VERSION 5.7 ;
  NOWIREEXTENSIONATPIN ON ;
  DIVIDERCHAR "/" ;
  BUSBITCHARS "[]" ;
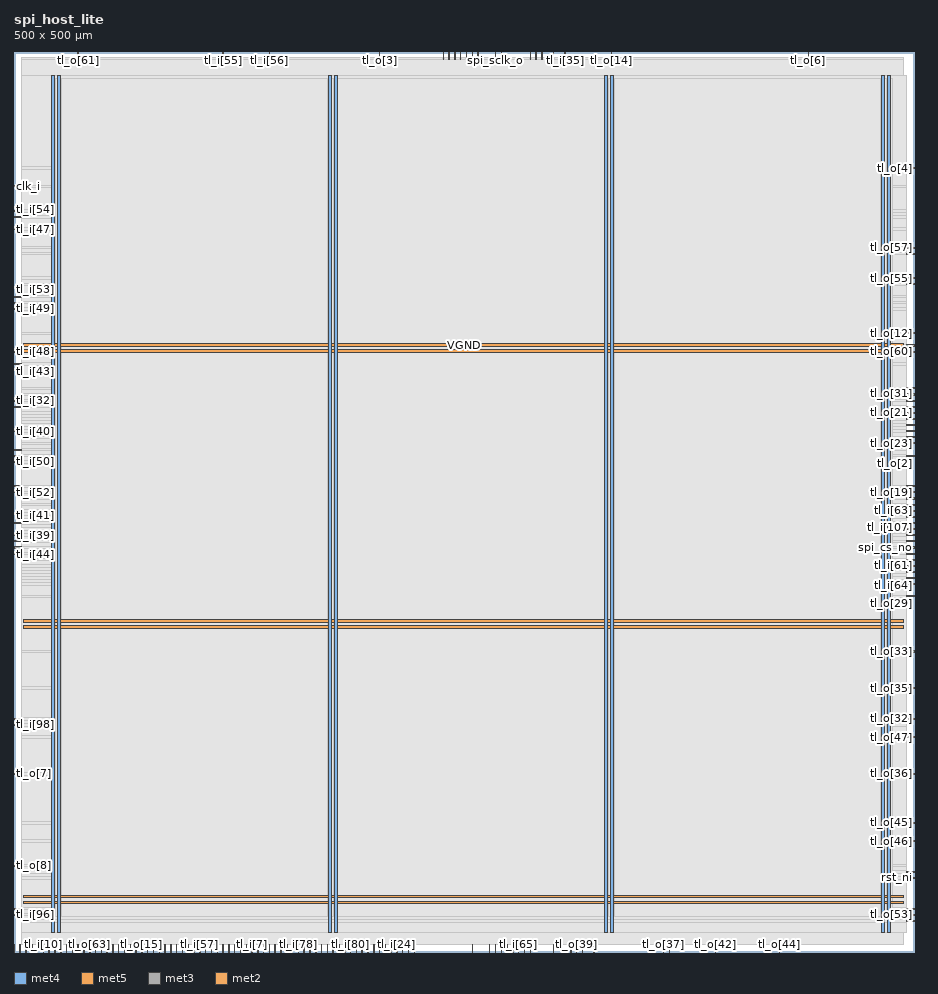
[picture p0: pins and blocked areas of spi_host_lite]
MACRO spi_host_lite
  CLASS BLOCK ;
  FOREIGN spi_host_lite ;
  ORIGIN 0.000 0.000 ;
  SIZE 500.000 BY 500.000 ;
  PIN VGND
    DIRECTION INOUT ;
    USE GROUND ;
    PORT
      LAYER met4 ;
        RECT 24.340 10.640 25.940 487.120 ;
    END
    PORT
      LAYER met4 ;
        RECT 177.940 10.640 179.540 487.120 ;
    END
    PORT
      LAYER met4 ;
        RECT 331.540 10.640 333.140 487.120 ;
    END
    PORT
      LAYER met4 ;
        RECT 485.140 10.640 486.740 487.120 ;
    END
    PORT
      LAYER met5 ;
        RECT 5.280 30.030 494.280 31.630 ;
    END
    PORT
      LAYER met5 ;
        RECT 5.280 183.210 494.280 184.810 ;
    END
    PORT
      LAYER met5 ;
        RECT 5.280 336.390 494.280 337.990 ;
    END
  END VGND
  PIN VPWR
    DIRECTION INOUT ;
    USE POWER ;
    PORT
      LAYER met4 ;
        RECT 21.040 10.640 22.640 487.120 ;
    END
    PORT
      LAYER met4 ;
        RECT 174.640 10.640 176.240 487.120 ;
    END
    PORT
      LAYER met4 ;
        RECT 328.240 10.640 329.840 487.120 ;
    END
    PORT
      LAYER met4 ;
        RECT 481.840 10.640 483.440 487.120 ;
    END
    PORT
      LAYER met5 ;
        RECT 5.280 26.730 494.280 28.330 ;
    END
    PORT
      LAYER met5 ;
        RECT 5.280 179.910 494.280 181.510 ;
    END
    PORT
      LAYER met5 ;
        RECT 5.280 333.090 494.280 334.690 ;
    END
  END VPWR
  PIN clk_i
    DIRECTION INPUT ;
    USE SIGNAL ;
    ANTENNAGATEAREA 1.286700 ;
    ANTENNADIFFAREA 0.434700 ;
    PORT
      LAYER met3 ;
        RECT 0.000 425.040 4.000 425.640 ;
    END
  END clk_i
  PIN intr_idle_o
    DIRECTION OUTPUT ;
    USE SIGNAL ;
    ANTENNADIFFAREA 0.445500 ;
    PORT
      LAYER met3 ;
        RECT 496.000 251.640 500.000 252.240 ;
    END
  END intr_idle_o
  PIN intr_rx_full_o
    DIRECTION OUTPUT ;
    USE SIGNAL ;
    ANTENNADIFFAREA 0.445500 ;
    PORT
      LAYER met2 ;
        RECT 254.470 0.000 254.750 4.000 ;
    END
  END intr_rx_full_o
  PIN intr_tx_empty_o
    DIRECTION OUTPUT ;
    USE SIGNAL ;
    ANTENNADIFFAREA 0.445500 ;
    PORT
      LAYER met2 ;
        RECT 277.010 0.000 277.290 4.000 ;
    END
  END intr_tx_empty_o
  PIN rst_ni
    DIRECTION INPUT ;
    USE SIGNAL ;
    ANTENNAGATEAREA 0.593700 ;
    ANTENNADIFFAREA 0.434700 ;
    PORT
      LAYER met3 ;
        RECT 496.000 40.840 500.000 41.440 ;
    END
  END rst_ni
  PIN spi_cs_no
    DIRECTION OUTPUT ;
    USE SIGNAL ;
    ANTENNADIFFAREA 0.445500 ;
    PORT
      LAYER met3 ;
        RECT 496.000 224.440 500.000 225.040 ;
    END
  END spi_cs_no
  PIN spi_miso_i
    DIRECTION INPUT ;
    USE SIGNAL ;
    ANTENNAGATEAREA 0.631200 ;
    ANTENNADIFFAREA 0.434700 ;
    PORT
      LAYER met2 ;
        RECT 270.570 0.000 270.850 4.000 ;
    END
  END spi_miso_i
  PIN spi_mosi_o
    DIRECTION OUTPUT ;
    USE SIGNAL ;
    ANTENNADIFFAREA 0.445500 ;
    PORT
      LAYER met3 ;
        RECT 0.000 360.440 4.000 361.040 ;
    END
  END spi_mosi_o
  PIN spi_sclk_o
    DIRECTION OUTPUT ;
    USE SIGNAL ;
    ANTENNADIFFAREA 0.445500 ;
    PORT
      LAYER met2 ;
        RECT 267.350 496.000 267.630 500.000 ;
    END
  END spi_sclk_o
  PIN tl_i[0]
    DIRECTION INPUT ;
    USE SIGNAL ;
    PORT
      LAYER met2 ;
        RECT 6.530 0.000 6.810 4.000 ;
    END
  END tl_i[0]
  PIN tl_i[100]
    DIRECTION INPUT ;
    USE SIGNAL ;
    ANTENNAGATEAREA 0.631200 ;
    ANTENNADIFFAREA 0.434700 ;
    PORT
      LAYER met2 ;
        RECT 238.370 496.000 238.650 500.000 ;
    END
  END tl_i[100]
  PIN tl_i[101]
    DIRECTION INPUT ;
    USE SIGNAL ;
    ANTENNAGATEAREA 0.631200 ;
    ANTENNADIFFAREA 0.434700 ;
    PORT
      LAYER met3 ;
        RECT 496.000 387.640 500.000 388.240 ;
    END
  END tl_i[101]
  PIN tl_i[102]
    DIRECTION INPUT ;
    USE SIGNAL ;
    ANTENNAGATEAREA 0.631200 ;
    ANTENNADIFFAREA 0.434700 ;
    PORT
      LAYER met2 ;
        RECT 248.030 496.000 248.310 500.000 ;
    END
  END tl_i[102]
  PIN tl_i[103]
    DIRECTION INPUT ;
    USE SIGNAL ;
    PORT
      LAYER met2 ;
        RECT 19.410 0.000 19.690 4.000 ;
    END
  END tl_i[103]
  PIN tl_i[104]
    DIRECTION INPUT ;
    USE SIGNAL ;
    PORT
      LAYER met2 ;
        RECT 9.750 0.000 10.030 4.000 ;
    END
  END tl_i[104]
  PIN tl_i[105]
    DIRECTION INPUT ;
    USE SIGNAL ;
    PORT
      LAYER met2 ;
        RECT 54.830 0.000 55.110 4.000 ;
    END
  END tl_i[105]
  PIN tl_i[106]
    DIRECTION INPUT ;
    USE SIGNAL ;
    PORT
      LAYER met2 ;
        RECT 12.970 0.000 13.250 4.000 ;
    END
  END tl_i[106]
  PIN tl_i[107]
    DIRECTION INPUT ;
    USE SIGNAL ;
    ANTENNAGATEAREA 0.560700 ;
    ANTENNADIFFAREA 0.434700 ;
    PORT
      LAYER met3 ;
        RECT 496.000 231.240 500.000 231.840 ;
    END
  END tl_i[107]
  PIN tl_i[108]
    DIRECTION INPUT ;
    USE SIGNAL ;
    ANTENNAGATEAREA 0.560700 ;
    ANTENNADIFFAREA 0.434700 ;
    PORT
      LAYER met3 ;
        RECT 496.000 238.040 500.000 238.640 ;
    END
  END tl_i[108]
  PIN tl_i[109]
    DIRECTION INPUT ;
    USE SIGNAL ;
    ANTENNAGATEAREA 0.631200 ;
    ANTENNADIFFAREA 0.434700 ;
    PORT
      LAYER met3 ;
        RECT 496.000 221.040 500.000 221.640 ;
    END
  END tl_i[109]
  PIN tl_i[10]
    DIRECTION INPUT ;
    USE SIGNAL ;
    PORT
      LAYER met2 ;
        RECT 16.190 0.000 16.470 4.000 ;
    END
  END tl_i[10]
  PIN tl_i[11]
    DIRECTION INPUT ;
    USE SIGNAL ;
    PORT
      LAYER met2 ;
        RECT 58.050 0.000 58.330 4.000 ;
    END
  END tl_i[11]
  PIN tl_i[12]
    DIRECTION INPUT ;
    USE SIGNAL ;
    PORT
      LAYER met2 ;
        RECT 215.830 0.000 216.110 4.000 ;
    END
  END tl_i[12]
  PIN tl_i[13]
    DIRECTION INPUT ;
    USE SIGNAL ;
    PORT
      LAYER met2 ;
        RECT 80.590 0.000 80.870 4.000 ;
    END
  END tl_i[13]
  PIN tl_i[14]
    DIRECTION INPUT ;
    USE SIGNAL ;
    PORT
      LAYER met2 ;
        RECT 51.610 0.000 51.890 4.000 ;
    END
  END tl_i[14]
  PIN tl_i[15]
    DIRECTION INPUT ;
    USE SIGNAL ;
    PORT
      LAYER met2 ;
        RECT 64.490 0.000 64.770 4.000 ;
    END
  END tl_i[15]
  PIN tl_i[16]
    DIRECTION INPUT ;
    USE SIGNAL ;
    PORT
      LAYER met2 ;
        RECT 48.390 0.000 48.670 4.000 ;
    END
  END tl_i[16]
  PIN tl_i[17]
    DIRECTION INPUT ;
    USE SIGNAL ;
    PORT
      LAYER met2 ;
        RECT 38.730 0.000 39.010 4.000 ;
    END
  END tl_i[17]
  PIN tl_i[18]
    DIRECTION INPUT ;
    USE SIGNAL ;
    PORT
      LAYER met2 ;
        RECT 29.070 0.000 29.350 4.000 ;
    END
  END tl_i[18]
  PIN tl_i[19]
    DIRECTION INPUT ;
    USE SIGNAL ;
    PORT
      LAYER met2 ;
        RECT 45.170 0.000 45.450 4.000 ;
    END
  END tl_i[19]
  PIN tl_i[1]
    DIRECTION INPUT ;
    USE SIGNAL ;
    PORT
      LAYER met2 ;
        RECT 61.270 0.000 61.550 4.000 ;
    END
  END tl_i[1]
  PIN tl_i[20]
    DIRECTION INPUT ;
    USE SIGNAL ;
    PORT
      LAYER met2 ;
        RECT 77.370 0.000 77.650 4.000 ;
    END
  END tl_i[20]
  PIN tl_i[21]
    DIRECTION INPUT ;
    USE SIGNAL ;
    PORT
      LAYER met2 ;
        RECT 90.250 0.000 90.530 4.000 ;
    END
  END tl_i[21]
  PIN tl_i[22]
    DIRECTION INPUT ;
    USE SIGNAL ;
    PORT
      LAYER met2 ;
        RECT 87.030 0.000 87.310 4.000 ;
    END
  END tl_i[22]
  PIN tl_i[23]
    DIRECTION INPUT ;
    USE SIGNAL ;
    PORT
      LAYER met2 ;
        RECT 3.310 0.000 3.590 4.000 ;
    END
  END tl_i[23]
  PIN tl_i[24]
    DIRECTION INPUT ;
    USE SIGNAL ;
    PORT
      LAYER met2 ;
        RECT 212.610 0.000 212.890 4.000 ;
    END
  END tl_i[24]
  PIN tl_i[25]
    DIRECTION INPUT ;
    USE SIGNAL ;
    ANTENNAGATEAREA 0.560700 ;
    ANTENNADIFFAREA 0.434700 ;
    PORT
      LAYER met2 ;
        RECT 202.950 0.000 203.230 4.000 ;
    END
  END tl_i[25]
  PIN tl_i[26]
    DIRECTION INPUT ;
    USE SIGNAL ;
    ANTENNAGATEAREA 0.560700 ;
    ANTENNADIFFAREA 0.434700 ;
    PORT
      LAYER met3 ;
        RECT 0.000 258.440 4.000 259.040 ;
    END
  END tl_i[26]
  PIN tl_i[27]
    DIRECTION INPUT ;
    USE SIGNAL ;
    ANTENNAGATEAREA 0.647700 ;
    ANTENNADIFFAREA 0.434700 ;
    PORT
      LAYER met3 ;
        RECT 0.000 278.840 4.000 279.440 ;
    END
  END tl_i[27]
  PIN tl_i[28]
    DIRECTION INPUT ;
    USE SIGNAL ;
    ANTENNAGATEAREA 0.560700 ;
    ANTENNADIFFAREA 0.434700 ;
    PORT
      LAYER met2 ;
        RECT 293.110 496.000 293.390 500.000 ;
    END
  END tl_i[28]
  PIN tl_i[29]
    DIRECTION INPUT ;
    USE SIGNAL ;
    ANTENNAGATEAREA 0.631200 ;
    ANTENNADIFFAREA 0.434700 ;
    PORT
      LAYER met2 ;
        RECT 289.890 496.000 290.170 500.000 ;
    END
  END tl_i[29]
  PIN tl_i[2]
    DIRECTION INPUT ;
    USE SIGNAL ;
    PORT
      LAYER met2 ;
        RECT 112.790 0.000 113.070 4.000 ;
    END
  END tl_i[2]
  PIN tl_i[30]
    DIRECTION INPUT ;
    USE SIGNAL ;
    ANTENNAGATEAREA 0.647700 ;
    ANTENNADIFFAREA 0.434700 ;
    PORT
      LAYER met2 ;
        RECT 257.690 496.000 257.970 500.000 ;
    END
  END tl_i[30]
  PIN tl_i[31]
    DIRECTION INPUT ;
    USE SIGNAL ;
    ANTENNAGATEAREA 0.647700 ;
    ANTENNADIFFAREA 0.434700 ;
    PORT
      LAYER met2 ;
        RECT 254.470 496.000 254.750 500.000 ;
    END
  END tl_i[31]
  PIN tl_i[32]
    DIRECTION INPUT ;
    USE SIGNAL ;
    ANTENNAGATEAREA 0.631200 ;
    ANTENNADIFFAREA 0.434700 ;
    PORT
      LAYER met3 ;
        RECT 0.000 306.040 4.000 306.640 ;
    END
  END tl_i[32]
  PIN tl_i[33]
    DIRECTION INPUT ;
    USE SIGNAL ;
    ANTENNAGATEAREA 0.631200 ;
    ANTENNADIFFAREA 0.434700 ;
    PORT
      LAYER met2 ;
        RECT 270.570 496.000 270.850 500.000 ;
    END
  END tl_i[33]
  PIN tl_i[34]
    DIRECTION INPUT ;
    USE SIGNAL ;
    ANTENNAGATEAREA 0.631200 ;
    ANTENNADIFFAREA 0.434700 ;
    PORT
      LAYER met2 ;
        RECT 244.810 496.000 245.090 500.000 ;
    END
  END tl_i[34]
  PIN tl_i[35]
    DIRECTION INPUT ;
    USE SIGNAL ;
    ANTENNAGATEAREA 0.631200 ;
    ANTENNADIFFAREA 0.434700 ;
    PORT
      LAYER met2 ;
        RECT 305.990 496.000 306.270 500.000 ;
    END
  END tl_i[35]
  PIN tl_i[36]
    DIRECTION INPUT ;
    USE SIGNAL ;
    ANTENNAGATEAREA 0.631200 ;
    ANTENNADIFFAREA 0.434700 ;
    PORT
      LAYER met2 ;
        RECT 286.670 496.000 286.950 500.000 ;
    END
  END tl_i[36]
  PIN tl_i[37]
    DIRECTION INPUT ;
    USE SIGNAL ;
    ANTENNAGATEAREA 0.631200 ;
    ANTENNADIFFAREA 0.434700 ;
    PORT
      LAYER met3 ;
        RECT 0.000 275.440 4.000 276.040 ;
    END
  END tl_i[37]
  PIN tl_i[38]
    DIRECTION INPUT ;
    USE SIGNAL ;
    ANTENNAGATEAREA 0.631200 ;
    ANTENNADIFFAREA 0.434700 ;
    PORT
      LAYER met2 ;
        RECT 299.550 496.000 299.830 500.000 ;
    END
  END tl_i[38]
  PIN tl_i[39]
    DIRECTION INPUT ;
    USE SIGNAL ;
    ANTENNAGATEAREA 0.631200 ;
    ANTENNADIFFAREA 0.434700 ;
    PORT
      LAYER met3 ;
        RECT 0.000 231.240 4.000 231.840 ;
    END
  END tl_i[39]
  PIN tl_i[3]
    DIRECTION INPUT ;
    USE SIGNAL ;
    PORT
      LAYER met2 ;
        RECT 196.510 0.000 196.790 4.000 ;
    END
  END tl_i[3]
  PIN tl_i[40]
    DIRECTION INPUT ;
    USE SIGNAL ;
    ANTENNAGATEAREA 0.631200 ;
    ANTENNADIFFAREA 0.434700 ;
    PORT
      LAYER met3 ;
        RECT 0.000 289.040 4.000 289.640 ;
    END
  END tl_i[40]
  PIN tl_i[41]
    DIRECTION INPUT ;
    USE SIGNAL ;
    ANTENNAGATEAREA 0.631200 ;
    ANTENNADIFFAREA 0.434700 ;
    PORT
      LAYER met3 ;
        RECT 0.000 238.040 4.000 238.640 ;
    END
  END tl_i[41]
  PIN tl_i[42]
    DIRECTION INPUT ;
    USE SIGNAL ;
    ANTENNAGATEAREA 0.631200 ;
    ANTENNADIFFAREA 0.434700 ;
    PORT
      LAYER met3 ;
        RECT 0.000 227.840 4.000 228.440 ;
    END
  END tl_i[42]
  PIN tl_i[43]
    DIRECTION INPUT ;
    USE SIGNAL ;
    ANTENNAGATEAREA 0.631200 ;
    ANTENNADIFFAREA 0.434700 ;
    PORT
      LAYER met3 ;
        RECT 0.000 326.440 4.000 327.040 ;
    END
  END tl_i[43]
  PIN tl_i[44]
    DIRECTION INPUT ;
    USE SIGNAL ;
    ANTENNAGATEAREA 0.560700 ;
    ANTENNADIFFAREA 0.434700 ;
    PORT
      LAYER met3 ;
        RECT 0.000 224.440 4.000 225.040 ;
    END
  END tl_i[44]
  PIN tl_i[45]
    DIRECTION INPUT ;
    USE SIGNAL ;
    ANTENNAGATEAREA 0.631200 ;
    ANTENNADIFFAREA 0.434700 ;
    PORT
      LAYER met3 ;
        RECT 0.000 302.640 4.000 303.240 ;
    END
  END tl_i[45]
  PIN tl_i[46]
    DIRECTION INPUT ;
    USE SIGNAL ;
    ANTENNAGATEAREA 0.631200 ;
    ANTENNADIFFAREA 0.434700 ;
    PORT
      LAYER met3 ;
        RECT 0.000 221.040 4.000 221.640 ;
    END
  END tl_i[46]
  PIN tl_i[47]
    DIRECTION INPUT ;
    USE SIGNAL ;
    ANTENNAGATEAREA 0.631200 ;
    ANTENNADIFFAREA 0.434700 ;
    PORT
      LAYER met3 ;
        RECT 0.000 401.240 4.000 401.840 ;
    END
  END tl_i[47]
  PIN tl_i[48]
    DIRECTION INPUT ;
    USE SIGNAL ;
    ANTENNAGATEAREA 0.631200 ;
    ANTENNADIFFAREA 0.434700 ;
    PORT
      LAYER met3 ;
        RECT 0.000 333.240 4.000 333.840 ;
    END
  END tl_i[48]
  PIN tl_i[49]
    DIRECTION INPUT ;
    USE SIGNAL ;
    ANTENNAGATEAREA 0.631200 ;
    ANTENNADIFFAREA 0.434700 ;
    PORT
      LAYER met3 ;
        RECT 0.000 357.040 4.000 357.640 ;
    END
  END tl_i[49]
  PIN tl_i[4]
    DIRECTION INPUT ;
    USE SIGNAL ;
    PORT
      LAYER met2 ;
        RECT 74.150 0.000 74.430 4.000 ;
    END
  END tl_i[4]
  PIN tl_i[50]
    DIRECTION INPUT ;
    USE SIGNAL ;
    ANTENNAGATEAREA 0.631200 ;
    ANTENNADIFFAREA 0.434700 ;
    PORT
      LAYER met3 ;
        RECT 0.000 272.040 4.000 272.640 ;
    END
  END tl_i[50]
  PIN tl_i[51]
    DIRECTION INPUT ;
    USE SIGNAL ;
    ANTENNAGATEAREA 0.631200 ;
    ANTENNADIFFAREA 0.434700 ;
    PORT
      LAYER met3 ;
        RECT 0.000 411.440 4.000 412.040 ;
    END
  END tl_i[51]
  PIN tl_i[52]
    DIRECTION INPUT ;
    USE SIGNAL ;
    ANTENNAGATEAREA 0.631200 ;
    ANTENNADIFFAREA 0.434700 ;
    PORT
      LAYER met3 ;
        RECT 0.000 255.040 4.000 255.640 ;
    END
  END tl_i[52]
  PIN tl_i[53]
    DIRECTION INPUT ;
    USE SIGNAL ;
    ANTENNAGATEAREA 0.560700 ;
    ANTENNADIFFAREA 0.434700 ;
    PORT
      LAYER met3 ;
        RECT 0.000 363.840 4.000 364.440 ;
    END
  END tl_i[53]
  PIN tl_i[54]
    DIRECTION INPUT ;
    USE SIGNAL ;
    ANTENNAGATEAREA 0.631200 ;
    ANTENNADIFFAREA 0.434700 ;
    PORT
      LAYER met3 ;
        RECT 0.000 408.040 4.000 408.640 ;
    END
  END tl_i[54]
  PIN tl_i[55]
    DIRECTION INPUT ;
    USE SIGNAL ;
    ANTENNAGATEAREA 0.631200 ;
    ANTENNADIFFAREA 0.434700 ;
    PORT
      LAYER met2 ;
        RECT 116.010 496.000 116.290 500.000 ;
    END
  END tl_i[55]
  PIN tl_i[56]
    DIRECTION INPUT ;
    USE SIGNAL ;
    ANTENNAGATEAREA 0.560700 ;
    ANTENNADIFFAREA 0.434700 ;
    PORT
      LAYER met2 ;
        RECT 141.770 496.000 142.050 500.000 ;
    END
  END tl_i[56]
  PIN tl_i[57]
    DIRECTION INPUT ;
    USE SIGNAL ;
    PORT
      LAYER met2 ;
        RECT 103.130 0.000 103.410 4.000 ;
    END
  END tl_i[57]
  PIN tl_i[58]
    DIRECTION INPUT ;
    USE SIGNAL ;
    PORT
      LAYER met2 ;
        RECT 138.550 0.000 138.830 4.000 ;
    END
  END tl_i[58]
  PIN tl_i[59]
    DIRECTION INPUT ;
    USE SIGNAL ;
    PORT
      LAYER met2 ;
        RECT 83.810 0.000 84.090 4.000 ;
    END
  END tl_i[59]
  PIN tl_i[5]
    DIRECTION INPUT ;
    USE SIGNAL ;
    PORT
      LAYER met2 ;
        RECT 219.050 0.000 219.330 4.000 ;
    END
  END tl_i[5]
  PIN tl_i[60]
    DIRECTION INPUT ;
    USE SIGNAL ;
    PORT
      LAYER met2 ;
        RECT 135.330 0.000 135.610 4.000 ;
    END
  END tl_i[60]
  PIN tl_i[61]
    DIRECTION INPUT ;
    USE SIGNAL ;
    ANTENNAGATEAREA 0.593700 ;
    ANTENNADIFFAREA 0.434700 ;
    PORT
      LAYER met3 ;
        RECT 496.000 214.240 500.000 214.840 ;
    END
  END tl_i[61]
  PIN tl_i[62]
    DIRECTION INPUT ;
    USE SIGNAL ;
    ANTENNAGATEAREA 0.647700 ;
    ANTENNADIFFAREA 0.434700 ;
    PORT
      LAYER met3 ;
        RECT 496.000 210.840 500.000 211.440 ;
    END
  END tl_i[62]
  PIN tl_i[63]
    DIRECTION INPUT ;
    USE SIGNAL ;
    ANTENNAGATEAREA 0.647700 ;
    ANTENNADIFFAREA 0.434700 ;
    PORT
      LAYER met3 ;
        RECT 496.000 244.840 500.000 245.440 ;
    END
  END tl_i[63]
  PIN tl_i[64]
    DIRECTION INPUT ;
    USE SIGNAL ;
    ANTENNAGATEAREA 0.593700 ;
    ANTENNADIFFAREA 0.434700 ;
    PORT
      LAYER met3 ;
        RECT 496.000 207.440 500.000 208.040 ;
    END
  END tl_i[64]
  PIN tl_i[65]
    DIRECTION INPUT ;
    USE SIGNAL ;
    ANTENNAGATEAREA 0.593700 ;
    ANTENNADIFFAREA 0.434700 ;
    PORT
      LAYER met2 ;
        RECT 280.230 0.000 280.510 4.000 ;
    END
  END tl_i[65]
  PIN tl_i[66]
    DIRECTION INPUT ;
    USE SIGNAL ;
    ANTENNAGATEAREA 0.647700 ;
    ANTENNADIFFAREA 0.434700 ;
    PORT
      LAYER met2 ;
        RECT 264.130 0.000 264.410 4.000 ;
    END
  END tl_i[66]
  PIN tl_i[67]
    DIRECTION INPUT ;
    USE SIGNAL ;
    ANTENNAGATEAREA 0.593700 ;
    ANTENNADIFFAREA 0.434700 ;
    PORT
      LAYER met2 ;
        RECT 273.790 0.000 274.070 4.000 ;
    END
  END tl_i[67]
  PIN tl_i[68]
    DIRECTION INPUT ;
    USE SIGNAL ;
    ANTENNAGATEAREA 0.647700 ;
    ANTENNADIFFAREA 0.434700 ;
    PORT
      LAYER met2 ;
        RECT 267.350 0.000 267.630 4.000 ;
    END
  END tl_i[68]
  PIN tl_i[69]
    DIRECTION INPUT ;
    USE SIGNAL ;
    PORT
      LAYER met2 ;
        RECT 125.670 0.000 125.950 4.000 ;
    END
  END tl_i[69]
  PIN tl_i[6]
    DIRECTION INPUT ;
    USE SIGNAL ;
    PORT
      LAYER met2 ;
        RECT 209.390 0.000 209.670 4.000 ;
    END
  END tl_i[6]
  PIN tl_i[70]
    DIRECTION INPUT ;
    USE SIGNAL ;
    PORT
      LAYER met2 ;
        RECT 99.910 0.000 100.190 4.000 ;
    END
  END tl_i[70]
  PIN tl_i[71]
    DIRECTION INPUT ;
    USE SIGNAL ;
    PORT
      LAYER met2 ;
        RECT 128.890 0.000 129.170 4.000 ;
    END
  END tl_i[71]
  PIN tl_i[72]
    DIRECTION INPUT ;
    USE SIGNAL ;
    PORT
      LAYER met2 ;
        RECT 0.090 0.000 0.370 4.000 ;
    END
  END tl_i[72]
  PIN tl_i[73]
    DIRECTION INPUT ;
    USE SIGNAL ;
    PORT
      LAYER met2 ;
        RECT 109.570 0.000 109.850 4.000 ;
    END
  END tl_i[73]
  PIN tl_i[74]
    DIRECTION INPUT ;
    USE SIGNAL ;
    PORT
      LAYER met2 ;
        RECT 151.430 0.000 151.710 4.000 ;
    END
  END tl_i[74]
  PIN tl_i[75]
    DIRECTION INPUT ;
    USE SIGNAL ;
    PORT
      LAYER met2 ;
        RECT 116.010 0.000 116.290 4.000 ;
    END
  END tl_i[75]
  PIN tl_i[76]
    DIRECTION INPUT ;
    USE SIGNAL ;
    PORT
      LAYER met2 ;
        RECT 119.230 0.000 119.510 4.000 ;
    END
  END tl_i[76]
  PIN tl_i[77]
    DIRECTION INPUT ;
    USE SIGNAL ;
    PORT
      LAYER met2 ;
        RECT 25.850 0.000 26.130 4.000 ;
    END
  END tl_i[77]
  PIN tl_i[78]
    DIRECTION INPUT ;
    USE SIGNAL ;
    PORT
      LAYER met2 ;
        RECT 157.870 0.000 158.150 4.000 ;
    END
  END tl_i[78]
  PIN tl_i[79]
    DIRECTION INPUT ;
    USE SIGNAL ;
    PORT
      LAYER met2 ;
        RECT 222.270 0.000 222.550 4.000 ;
    END
  END tl_i[79]
  PIN tl_i[7]
    DIRECTION INPUT ;
    USE SIGNAL ;
    PORT
      LAYER met2 ;
        RECT 132.110 0.000 132.390 4.000 ;
    END
  END tl_i[7]
  PIN tl_i[80]
    DIRECTION INPUT ;
    USE SIGNAL ;
    PORT
      LAYER met2 ;
        RECT 186.850 0.000 187.130 4.000 ;
    END
  END tl_i[80]
  PIN tl_i[81]
    DIRECTION INPUT ;
    USE SIGNAL ;
    PORT
      LAYER met2 ;
        RECT 199.730 0.000 200.010 4.000 ;
    END
  END tl_i[81]
  PIN tl_i[82]
    DIRECTION INPUT ;
    USE SIGNAL ;
    PORT
      LAYER met2 ;
        RECT 141.770 0.000 142.050 4.000 ;
    END
  END tl_i[82]
  PIN tl_i[83]
    DIRECTION INPUT ;
    USE SIGNAL ;
    PORT
      LAYER met2 ;
        RECT 144.990 0.000 145.270 4.000 ;
    END
  END tl_i[83]
  PIN tl_i[84]
    DIRECTION INPUT ;
    USE SIGNAL ;
    PORT
      LAYER met2 ;
        RECT 148.210 0.000 148.490 4.000 ;
    END
  END tl_i[84]
  PIN tl_i[85]
    DIRECTION INPUT ;
    USE SIGNAL ;
    PORT
      LAYER met2 ;
        RECT 173.970 0.000 174.250 4.000 ;
    END
  END tl_i[85]
  PIN tl_i[86]
    DIRECTION INPUT ;
    USE SIGNAL ;
    PORT
      LAYER met2 ;
        RECT 154.650 0.000 154.930 4.000 ;
    END
  END tl_i[86]
  PIN tl_i[87]
    DIRECTION INPUT ;
    USE SIGNAL ;
    PORT
      LAYER met2 ;
        RECT 190.070 0.000 190.350 4.000 ;
    END
  END tl_i[87]
  PIN tl_i[88]
    DIRECTION INPUT ;
    USE SIGNAL ;
    PORT
      LAYER met2 ;
        RECT 161.090 0.000 161.370 4.000 ;
    END
  END tl_i[88]
  PIN tl_i[89]
    DIRECTION INPUT ;
    USE SIGNAL ;
    PORT
      LAYER met2 ;
        RECT 164.310 0.000 164.590 4.000 ;
    END
  END tl_i[89]
  PIN tl_i[8]
    DIRECTION INPUT ;
    USE SIGNAL ;
    PORT
      LAYER met2 ;
        RECT 35.510 0.000 35.790 4.000 ;
    END
  END tl_i[8]
  PIN tl_i[90]
    DIRECTION INPUT ;
    USE SIGNAL ;
    PORT
      LAYER met2 ;
        RECT 206.170 0.000 206.450 4.000 ;
    END
  END tl_i[90]
  PIN tl_i[91]
    DIRECTION INPUT ;
    USE SIGNAL ;
    PORT
      LAYER met2 ;
        RECT 193.290 0.000 193.570 4.000 ;
    END
  END tl_i[91]
  PIN tl_i[92]
    DIRECTION INPUT ;
    USE SIGNAL ;
    PORT
      LAYER met2 ;
        RECT 177.190 0.000 177.470 4.000 ;
    END
  END tl_i[92]
  PIN tl_i[93]
    DIRECTION INPUT ;
    USE SIGNAL ;
    ANTENNAGATEAREA 0.631200 ;
    ANTENNADIFFAREA 0.434700 ;
    PORT
      LAYER met2 ;
        RECT 93.470 0.000 93.750 4.000 ;
    END
  END tl_i[93]
  PIN tl_i[94]
    DIRECTION INPUT ;
    USE SIGNAL ;
    ANTENNAGATEAREA 0.631200 ;
    ANTENNADIFFAREA 0.434700 ;
    PORT
      LAYER met2 ;
        RECT 167.530 0.000 167.810 4.000 ;
    END
  END tl_i[94]
  PIN tl_i[95]
    DIRECTION INPUT ;
    USE SIGNAL ;
    ANTENNAGATEAREA 0.631200 ;
    ANTENNADIFFAREA 0.434700 ;
    PORT
      LAYER met2 ;
        RECT 180.410 0.000 180.690 4.000 ;
    END
  END tl_i[95]
  PIN tl_i[96]
    DIRECTION INPUT ;
    USE SIGNAL ;
    ANTENNAGATEAREA 0.631200 ;
    ANTENNADIFFAREA 0.434700 ;
    PORT
      LAYER met3 ;
        RECT 0.000 20.440 4.000 21.040 ;
    END
  END tl_i[96]
  PIN tl_i[97]
    DIRECTION INPUT ;
    USE SIGNAL ;
    ANTENNAGATEAREA 0.631200 ;
    ANTENNADIFFAREA 0.434700 ;
    PORT
      LAYER met3 ;
        RECT 496.000 17.040 500.000 17.640 ;
    END
  END tl_i[97]
  PIN tl_i[98]
    DIRECTION INPUT ;
    USE SIGNAL ;
    ANTENNAGATEAREA 0.631200 ;
    ANTENNADIFFAREA 0.434700 ;
    PORT
      LAYER met3 ;
        RECT 0.000 125.840 4.000 126.440 ;
    END
  END tl_i[98]
  PIN tl_i[99]
    DIRECTION INPUT ;
    USE SIGNAL ;
    ANTENNAGATEAREA 0.631200 ;
    ANTENNADIFFAREA 0.434700 ;
    PORT
      LAYER met3 ;
        RECT 496.000 370.640 500.000 371.240 ;
    END
  END tl_i[99]
  PIN tl_i[9]
    DIRECTION INPUT ;
    USE SIGNAL ;
    PORT
      LAYER met2 ;
        RECT 22.630 0.000 22.910 4.000 ;
    END
  END tl_i[9]
  PIN tl_o[0]
    DIRECTION OUTPUT ;
    USE SIGNAL ;
    PORT
      LAYER met2 ;
        RECT 122.450 0.000 122.730 4.000 ;
    END
  END tl_o[0]
  PIN tl_o[10]
    DIRECTION OUTPUT ;
    USE SIGNAL ;
    PORT
      LAYER met2 ;
        RECT 309.210 0.000 309.490 4.000 ;
    END
  END tl_o[10]
  PIN tl_o[11]
    DIRECTION OUTPUT ;
    USE SIGNAL ;
    PORT
      LAYER met3 ;
        RECT 496.000 336.640 500.000 337.240 ;
    END
  END tl_o[11]
  PIN tl_o[12]
    DIRECTION OUTPUT ;
    USE SIGNAL ;
    PORT
      LAYER met3 ;
        RECT 496.000 343.440 500.000 344.040 ;
    END
  END tl_o[12]
  PIN tl_o[13]
    DIRECTION OUTPUT ;
    USE SIGNAL ;
    PORT
      LAYER met3 ;
        RECT 496.000 23.840 500.000 24.440 ;
    END
  END tl_o[13]
  PIN tl_o[14]
    DIRECTION OUTPUT ;
    USE SIGNAL ;
    PORT
      LAYER met2 ;
        RECT 331.750 496.000 332.030 500.000 ;
    END
  END tl_o[14]
  PIN tl_o[15]
    DIRECTION OUTPUT ;
    USE SIGNAL ;
    PORT
      LAYER met2 ;
        RECT 70.930 0.000 71.210 4.000 ;
    END
  END tl_o[15]
  PIN tl_o[16]
    DIRECTION OUTPUT ;
    USE SIGNAL ;
    ANTENNADIFFAREA 0.445500 ;
    PORT
      LAYER met2 ;
        RECT 299.550 0.000 299.830 4.000 ;
    END
  END tl_o[16]
  PIN tl_o[17]
    DIRECTION OUTPUT ;
    USE SIGNAL ;
    ANTENNADIFFAREA 0.445500 ;
    PORT
      LAYER met3 ;
        RECT 496.000 241.440 500.000 242.040 ;
    END
  END tl_o[17]
  PIN tl_o[18]
    DIRECTION OUTPUT ;
    USE SIGNAL ;
    ANTENNADIFFAREA 0.445500 ;
    PORT
      LAYER met3 ;
        RECT 496.000 248.240 500.000 248.840 ;
    END
  END tl_o[18]
  PIN tl_o[19]
    DIRECTION OUTPUT ;
    USE SIGNAL ;
    ANTENNADIFFAREA 0.445500 ;
    PORT
      LAYER met3 ;
        RECT 496.000 255.040 500.000 255.640 ;
    END
  END tl_o[19]
  PIN tl_o[1]
    DIRECTION OUTPUT ;
    USE SIGNAL ;
    ANTENNADIFFAREA 0.445500 ;
    PORT
      LAYER met2 ;
        RECT 286.670 0.000 286.950 4.000 ;
    END
  END tl_o[1]
  PIN tl_o[20]
    DIRECTION OUTPUT ;
    USE SIGNAL ;
    ANTENNADIFFAREA 0.445500 ;
    PORT
      LAYER met3 ;
        RECT 496.000 258.440 500.000 259.040 ;
    END
  END tl_o[20]
  PIN tl_o[21]
    DIRECTION OUTPUT ;
    USE SIGNAL ;
    ANTENNADIFFAREA 0.445500 ;
    PORT
      LAYER met3 ;
        RECT 496.000 299.240 500.000 299.840 ;
    END
  END tl_o[21]
  PIN tl_o[22]
    DIRECTION OUTPUT ;
    USE SIGNAL ;
    ANTENNADIFFAREA 0.445500 ;
    PORT
      LAYER met3 ;
        RECT 496.000 295.840 500.000 296.440 ;
    END
  END tl_o[22]
  PIN tl_o[23]
    DIRECTION OUTPUT ;
    USE SIGNAL ;
    ANTENNADIFFAREA 0.445500 ;
    PORT
      LAYER met3 ;
        RECT 496.000 282.240 500.000 282.840 ;
    END
  END tl_o[23]
  PIN tl_o[24]
    DIRECTION OUTPUT ;
    USE SIGNAL ;
    ANTENNADIFFAREA 0.445500 ;
    PORT
      LAYER met3 ;
        RECT 496.000 312.840 500.000 313.440 ;
    END
  END tl_o[24]
  PIN tl_o[25]
    DIRECTION OUTPUT ;
    USE SIGNAL ;
    ANTENNADIFFAREA 0.445500 ;
    PORT
      LAYER met3 ;
        RECT 496.000 289.040 500.000 289.640 ;
    END
  END tl_o[25]
  PIN tl_o[26]
    DIRECTION OUTPUT ;
    USE SIGNAL ;
    ANTENNADIFFAREA 0.445500 ;
    PORT
      LAYER met3 ;
        RECT 496.000 285.640 500.000 286.240 ;
    END
  END tl_o[26]
  PIN tl_o[27]
    DIRECTION OUTPUT ;
    USE SIGNAL ;
    ANTENNADIFFAREA 0.445500 ;
    PORT
      LAYER met3 ;
        RECT 496.000 302.640 500.000 303.240 ;
    END
  END tl_o[27]
  PIN tl_o[28]
    DIRECTION OUTPUT ;
    USE SIGNAL ;
    ANTENNADIFFAREA 0.445500 ;
    PORT
      LAYER met3 ;
        RECT 496.000 292.440 500.000 293.040 ;
    END
  END tl_o[28]
  PIN tl_o[29]
    DIRECTION OUTPUT ;
    USE SIGNAL ;
    ANTENNADIFFAREA 0.445500 ;
    PORT
      LAYER met3 ;
        RECT 496.000 197.240 500.000 197.840 ;
    END
  END tl_o[29]
  PIN tl_o[2]
    DIRECTION OUTPUT ;
    USE SIGNAL ;
    PORT
      LAYER met3 ;
        RECT 496.000 275.440 500.000 276.040 ;
    END
  END tl_o[2]
  PIN tl_o[30]
    DIRECTION OUTPUT ;
    USE SIGNAL ;
    ANTENNADIFFAREA 0.445500 ;
    PORT
      LAYER met3 ;
        RECT 496.000 234.640 500.000 235.240 ;
    END
  END tl_o[30]
  PIN tl_o[31]
    DIRECTION OUTPUT ;
    USE SIGNAL ;
    ANTENNADIFFAREA 0.445500 ;
    PORT
      LAYER met3 ;
        RECT 496.000 306.040 500.000 306.640 ;
    END
  END tl_o[31]
  PIN tl_o[32]
    DIRECTION OUTPUT ;
    USE SIGNAL ;
    ANTENNADIFFAREA 0.445500 ;
    PORT
      LAYER met3 ;
        RECT 496.000 129.240 500.000 129.840 ;
    END
  END tl_o[32]
  PIN tl_o[33]
    DIRECTION OUTPUT ;
    USE SIGNAL ;
    ANTENNADIFFAREA 0.445500 ;
    PORT
      LAYER met3 ;
        RECT 496.000 166.640 500.000 167.240 ;
    END
  END tl_o[33]
  PIN tl_o[34]
    DIRECTION OUTPUT ;
    USE SIGNAL ;
    ANTENNADIFFAREA 0.445500 ;
    PORT
      LAYER met3 ;
        RECT 496.000 204.040 500.000 204.640 ;
    END
  END tl_o[34]
  PIN tl_o[35]
    DIRECTION OUTPUT ;
    USE SIGNAL ;
    ANTENNADIFFAREA 0.445500 ;
    PORT
      LAYER met3 ;
        RECT 496.000 146.240 500.000 146.840 ;
    END
  END tl_o[35]
  PIN tl_o[36]
    DIRECTION OUTPUT ;
    USE SIGNAL ;
    ANTENNADIFFAREA 0.445500 ;
    PORT
      LAYER met3 ;
        RECT 496.000 98.640 500.000 99.240 ;
    END
  END tl_o[36]
  PIN tl_o[37]
    DIRECTION OUTPUT ;
    USE SIGNAL ;
    ANTENNADIFFAREA 0.445500 ;
    PORT
      LAYER met2 ;
        RECT 360.730 0.000 361.010 4.000 ;
    END
  END tl_o[37]
  PIN tl_o[38]
    DIRECTION OUTPUT ;
    USE SIGNAL ;
    ANTENNADIFFAREA 0.445500 ;
    PORT
      LAYER met2 ;
        RECT 363.950 0.000 364.230 4.000 ;
    END
  END tl_o[38]
  PIN tl_o[39]
    DIRECTION OUTPUT ;
    USE SIGNAL ;
    ANTENNADIFFAREA 0.445500 ;
    PORT
      LAYER met2 ;
        RECT 312.430 0.000 312.710 4.000 ;
    END
  END tl_o[39]
  PIN tl_o[3]
    DIRECTION OUTPUT ;
    USE SIGNAL ;
    PORT
      LAYER met2 ;
        RECT 202.950 496.000 203.230 500.000 ;
    END
  END tl_o[3]
  PIN tl_o[40]
    DIRECTION OUTPUT ;
    USE SIGNAL ;
    ANTENNADIFFAREA 0.445500 ;
    PORT
      LAYER met2 ;
        RECT 315.650 0.000 315.930 4.000 ;
    END
  END tl_o[40]
  PIN tl_o[41]
    DIRECTION OUTPUT ;
    USE SIGNAL ;
    ANTENNADIFFAREA 0.445500 ;
    PORT
      LAYER met2 ;
        RECT 322.090 0.000 322.370 4.000 ;
    END
  END tl_o[41]
  PIN tl_o[42]
    DIRECTION OUTPUT ;
    USE SIGNAL ;
    ANTENNADIFFAREA 0.445500 ;
    PORT
      LAYER met2 ;
        RECT 389.710 0.000 389.990 4.000 ;
    END
  END tl_o[42]
  PIN tl_o[43]
    DIRECTION OUTPUT ;
    USE SIGNAL ;
    ANTENNADIFFAREA 0.445500 ;
    PORT
      LAYER met3 ;
        RECT 496.000 44.240 500.000 44.840 ;
    END
  END tl_o[43]
  PIN tl_o[44]
    DIRECTION OUTPUT ;
    USE SIGNAL ;
    ANTENNADIFFAREA 0.445500 ;
    PORT
      LAYER met2 ;
        RECT 425.130 0.000 425.410 4.000 ;
    END
  END tl_o[44]
  PIN tl_o[45]
    DIRECTION OUTPUT ;
    USE SIGNAL ;
    ANTENNADIFFAREA 0.445500 ;
    PORT
      LAYER met3 ;
        RECT 496.000 71.440 500.000 72.040 ;
    END
  END tl_o[45]
  PIN tl_o[46]
    DIRECTION OUTPUT ;
    USE SIGNAL ;
    ANTENNADIFFAREA 0.445500 ;
    PORT
      LAYER met3 ;
        RECT 496.000 61.240 500.000 61.840 ;
    END
  END tl_o[46]
  PIN tl_o[47]
    DIRECTION OUTPUT ;
    USE SIGNAL ;
    ANTENNADIFFAREA 0.445500 ;
    PORT
      LAYER met3 ;
        RECT 496.000 119.040 500.000 119.640 ;
    END
  END tl_o[47]
  PIN tl_o[48]
    DIRECTION OUTPUT ;
    USE SIGNAL ;
    PORT
      LAYER met2 ;
        RECT 32.290 0.000 32.570 4.000 ;
    END
  END tl_o[48]
  PIN tl_o[49]
    DIRECTION OUTPUT ;
    USE SIGNAL ;
    ANTENNADIFFAREA 0.445500 ;
    PORT
      LAYER met2 ;
        RECT 96.690 0.000 96.970 4.000 ;
    END
  END tl_o[49]
  PIN tl_o[4]
    DIRECTION OUTPUT ;
    USE SIGNAL ;
    PORT
      LAYER met3 ;
        RECT 496.000 435.240 500.000 435.840 ;
    END
  END tl_o[4]
  PIN tl_o[50]
    DIRECTION OUTPUT ;
    USE SIGNAL ;
    ANTENNADIFFAREA 0.445500 ;
    PORT
      LAYER met2 ;
        RECT 170.750 0.000 171.030 4.000 ;
    END
  END tl_o[50]
  PIN tl_o[51]
    DIRECTION OUTPUT ;
    USE SIGNAL ;
    ANTENNADIFFAREA 0.445500 ;
    PORT
      LAYER met2 ;
        RECT 183.630 0.000 183.910 4.000 ;
    END
  END tl_o[51]
  PIN tl_o[52]
    DIRECTION OUTPUT ;
    USE SIGNAL ;
    ANTENNADIFFAREA 0.445500 ;
    PORT
      LAYER met3 ;
        RECT 0.000 23.840 4.000 24.440 ;
    END
  END tl_o[52]
  PIN tl_o[53]
    DIRECTION OUTPUT ;
    USE SIGNAL ;
    ANTENNADIFFAREA 0.445500 ;
    PORT
      LAYER met3 ;
        RECT 496.000 20.440 500.000 21.040 ;
    END
  END tl_o[53]
  PIN tl_o[54]
    DIRECTION OUTPUT ;
    USE SIGNAL ;
    ANTENNADIFFAREA 0.445500 ;
    PORT
      LAYER met3 ;
        RECT 0.000 129.240 4.000 129.840 ;
    END
  END tl_o[54]
  PIN tl_o[55]
    DIRECTION OUTPUT ;
    USE SIGNAL ;
    ANTENNADIFFAREA 0.445500 ;
    PORT
      LAYER met3 ;
        RECT 496.000 374.040 500.000 374.640 ;
    END
  END tl_o[55]
  PIN tl_o[56]
    DIRECTION OUTPUT ;
    USE SIGNAL ;
    ANTENNADIFFAREA 0.445500 ;
    PORT
      LAYER met2 ;
        RECT 241.590 496.000 241.870 500.000 ;
    END
  END tl_o[56]
  PIN tl_o[57]
    DIRECTION OUTPUT ;
    USE SIGNAL ;
    ANTENNADIFFAREA 0.445500 ;
    PORT
      LAYER met3 ;
        RECT 496.000 391.040 500.000 391.640 ;
    END
  END tl_o[57]
  PIN tl_o[58]
    DIRECTION OUTPUT ;
    USE SIGNAL ;
    ANTENNADIFFAREA 0.445500 ;
    PORT
      LAYER met2 ;
        RECT 251.250 496.000 251.530 500.000 ;
    END
  END tl_o[58]
  PIN tl_o[59]
    DIRECTION OUTPUT ;
    USE SIGNAL ;
    PORT
      LAYER met2 ;
        RECT 67.710 0.000 67.990 4.000 ;
    END
  END tl_o[59]
  PIN tl_o[5]
    DIRECTION OUTPUT ;
    USE SIGNAL ;
    PORT
      LAYER met2 ;
        RECT 106.350 0.000 106.630 4.000 ;
    END
  END tl_o[5]
  PIN tl_o[60]
    DIRECTION OUTPUT ;
    USE SIGNAL ;
    PORT
      LAYER met3 ;
        RECT 496.000 333.240 500.000 333.840 ;
    END
  END tl_o[60]
  PIN tl_o[61]
    DIRECTION OUTPUT ;
    USE SIGNAL ;
    PORT
      LAYER met2 ;
        RECT 35.510 496.000 35.790 500.000 ;
    END
  END tl_o[61]
  PIN tl_o[62]
    DIRECTION OUTPUT ;
    USE SIGNAL ;
    ANTENNADIFFAREA 0.445500 ;
    PORT
      LAYER met3 ;
        RECT 496.000 227.840 500.000 228.440 ;
    END
  END tl_o[62]
  PIN tl_o[63]
    DIRECTION OUTPUT ;
    USE SIGNAL ;
    PORT
      LAYER met2 ;
        RECT 41.950 0.000 42.230 4.000 ;
    END
  END tl_o[63]
  PIN tl_o[64]
    DIRECTION OUTPUT ;
    USE SIGNAL ;
    PORT
      LAYER met2 ;
        RECT 283.450 0.000 283.730 4.000 ;
    END
  END tl_o[64]
  PIN tl_o[65]
    DIRECTION OUTPUT ;
    USE SIGNAL ;
    ANTENNADIFFAREA 0.445500 ;
    PORT
      LAYER met3 ;
        RECT 496.000 217.640 500.000 218.240 ;
    END
  END tl_o[65]
  PIN tl_o[6]
    DIRECTION OUTPUT ;
    USE SIGNAL ;
    PORT
      LAYER met2 ;
        RECT 441.230 496.000 441.510 500.000 ;
    END
  END tl_o[6]
  PIN tl_o[7]
    DIRECTION OUTPUT ;
    USE SIGNAL ;
    PORT
      LAYER met3 ;
        RECT 0.000 98.640 4.000 99.240 ;
    END
  END tl_o[7]
  PIN tl_o[8]
    DIRECTION OUTPUT ;
    USE SIGNAL ;
    PORT
      LAYER met3 ;
        RECT 0.000 47.640 4.000 48.240 ;
    END
  END tl_o[8]
  PIN tl_o[9]
    DIRECTION OUTPUT ;
    USE SIGNAL ;
    PORT
      LAYER met3 ;
        RECT 496.000 309.440 500.000 310.040 ;
    END
  END tl_o[9]
  OBS
      LAYER nwell ;
        RECT 5.330 10.795 494.230 487.070 ;
      LAYER li1 ;
        RECT 5.520 10.795 494.040 486.965 ;
      LAYER met1 ;
        RECT 4.210 10.640 494.430 487.120 ;
      LAYER met2 ;
        RECT 4.230 495.720 35.230 496.810 ;
        RECT 36.070 495.720 115.730 496.810 ;
        RECT 116.570 495.720 141.490 496.810 ;
        RECT 142.330 495.720 202.670 496.810 ;
        RECT 203.510 495.720 238.090 496.810 ;
        RECT 238.930 495.720 241.310 496.810 ;
        RECT 242.150 495.720 244.530 496.810 ;
        RECT 245.370 495.720 247.750 496.810 ;
        RECT 248.590 495.720 250.970 496.810 ;
        RECT 251.810 495.720 254.190 496.810 ;
        RECT 255.030 495.720 257.410 496.810 ;
        RECT 258.250 495.720 267.070 496.810 ;
        RECT 267.910 495.720 270.290 496.810 ;
        RECT 271.130 495.720 286.390 496.810 ;
        RECT 287.230 495.720 289.610 496.810 ;
        RECT 290.450 495.720 292.830 496.810 ;
        RECT 293.670 495.720 299.270 496.810 ;
        RECT 300.110 495.720 305.710 496.810 ;
        RECT 306.550 495.720 331.470 496.810 ;
        RECT 332.310 495.720 440.950 496.810 ;
        RECT 441.790 495.720 494.400 496.810 ;
        RECT 4.230 4.280 494.400 495.720 ;
        RECT 4.230 4.000 6.250 4.280 ;
        RECT 7.090 4.000 9.470 4.280 ;
        RECT 10.310 4.000 12.690 4.280 ;
        RECT 13.530 4.000 15.910 4.280 ;
        RECT 16.750 4.000 19.130 4.280 ;
        RECT 19.970 4.000 22.350 4.280 ;
        RECT 23.190 4.000 25.570 4.280 ;
        RECT 26.410 4.000 28.790 4.280 ;
        RECT 29.630 4.000 32.010 4.280 ;
        RECT 32.850 4.000 35.230 4.280 ;
        RECT 36.070 4.000 38.450 4.280 ;
        RECT 39.290 4.000 41.670 4.280 ;
        RECT 42.510 4.000 44.890 4.280 ;
        RECT 45.730 4.000 48.110 4.280 ;
        RECT 48.950 4.000 51.330 4.280 ;
        RECT 52.170 4.000 54.550 4.280 ;
        RECT 55.390 4.000 57.770 4.280 ;
        RECT 58.610 4.000 60.990 4.280 ;
        RECT 61.830 4.000 64.210 4.280 ;
        RECT 65.050 4.000 67.430 4.280 ;
        RECT 68.270 4.000 70.650 4.280 ;
        RECT 71.490 4.000 73.870 4.280 ;
        RECT 74.710 4.000 77.090 4.280 ;
        RECT 77.930 4.000 80.310 4.280 ;
        RECT 81.150 4.000 83.530 4.280 ;
        RECT 84.370 4.000 86.750 4.280 ;
        RECT 87.590 4.000 89.970 4.280 ;
        RECT 90.810 4.000 93.190 4.280 ;
        RECT 94.030 4.000 96.410 4.280 ;
        RECT 97.250 4.000 99.630 4.280 ;
        RECT 100.470 4.000 102.850 4.280 ;
        RECT 103.690 4.000 106.070 4.280 ;
        RECT 106.910 4.000 109.290 4.280 ;
        RECT 110.130 4.000 112.510 4.280 ;
        RECT 113.350 4.000 115.730 4.280 ;
        RECT 116.570 4.000 118.950 4.280 ;
        RECT 119.790 4.000 122.170 4.280 ;
        RECT 123.010 4.000 125.390 4.280 ;
        RECT 126.230 4.000 128.610 4.280 ;
        RECT 129.450 4.000 131.830 4.280 ;
        RECT 132.670 4.000 135.050 4.280 ;
        RECT 135.890 4.000 138.270 4.280 ;
        RECT 139.110 4.000 141.490 4.280 ;
        RECT 142.330 4.000 144.710 4.280 ;
        RECT 145.550 4.000 147.930 4.280 ;
        RECT 148.770 4.000 151.150 4.280 ;
        RECT 151.990 4.000 154.370 4.280 ;
        RECT 155.210 4.000 157.590 4.280 ;
        RECT 158.430 4.000 160.810 4.280 ;
        RECT 161.650 4.000 164.030 4.280 ;
        RECT 164.870 4.000 167.250 4.280 ;
        RECT 168.090 4.000 170.470 4.280 ;
        RECT 171.310 4.000 173.690 4.280 ;
        RECT 174.530 4.000 176.910 4.280 ;
        RECT 177.750 4.000 180.130 4.280 ;
        RECT 180.970 4.000 183.350 4.280 ;
        RECT 184.190 4.000 186.570 4.280 ;
        RECT 187.410 4.000 189.790 4.280 ;
        RECT 190.630 4.000 193.010 4.280 ;
        RECT 193.850 4.000 196.230 4.280 ;
        RECT 197.070 4.000 199.450 4.280 ;
        RECT 200.290 4.000 202.670 4.280 ;
        RECT 203.510 4.000 205.890 4.280 ;
        RECT 206.730 4.000 209.110 4.280 ;
        RECT 209.950 4.000 212.330 4.280 ;
        RECT 213.170 4.000 215.550 4.280 ;
        RECT 216.390 4.000 218.770 4.280 ;
        RECT 219.610 4.000 221.990 4.280 ;
        RECT 222.830 4.000 254.190 4.280 ;
        RECT 255.030 4.000 263.850 4.280 ;
        RECT 264.690 4.000 267.070 4.280 ;
        RECT 267.910 4.000 270.290 4.280 ;
        RECT 271.130 4.000 273.510 4.280 ;
        RECT 274.350 4.000 276.730 4.280 ;
        RECT 277.570 4.000 279.950 4.280 ;
        RECT 280.790 4.000 283.170 4.280 ;
        RECT 284.010 4.000 286.390 4.280 ;
        RECT 287.230 4.000 299.270 4.280 ;
        RECT 300.110 4.000 308.930 4.280 ;
        RECT 309.770 4.000 312.150 4.280 ;
        RECT 312.990 4.000 315.370 4.280 ;
        RECT 316.210 4.000 321.810 4.280 ;
        RECT 322.650 4.000 360.450 4.280 ;
        RECT 361.290 4.000 363.670 4.280 ;
        RECT 364.510 4.000 389.430 4.280 ;
        RECT 390.270 4.000 424.850 4.280 ;
        RECT 425.690 4.000 494.400 4.280 ;
      LAYER met3 ;
        RECT 3.990 436.240 496.000 487.045 ;
        RECT 3.990 434.840 495.600 436.240 ;
        RECT 3.990 426.040 496.000 434.840 ;
        RECT 4.400 424.640 496.000 426.040 ;
        RECT 3.990 412.440 496.000 424.640 ;
        RECT 4.400 411.040 496.000 412.440 ;
        RECT 3.990 409.040 496.000 411.040 ;
        RECT 4.400 407.640 496.000 409.040 ;
        RECT 3.990 402.240 496.000 407.640 ;
        RECT 4.400 400.840 496.000 402.240 ;
        RECT 3.990 392.040 496.000 400.840 ;
        RECT 3.990 390.640 495.600 392.040 ;
        RECT 3.990 388.640 496.000 390.640 ;
        RECT 3.990 387.240 495.600 388.640 ;
        RECT 3.990 375.040 496.000 387.240 ;
        RECT 3.990 373.640 495.600 375.040 ;
        RECT 3.990 371.640 496.000 373.640 ;
        RECT 3.990 370.240 495.600 371.640 ;
        RECT 3.990 364.840 496.000 370.240 ;
        RECT 4.400 363.440 496.000 364.840 ;
        RECT 3.990 361.440 496.000 363.440 ;
        RECT 4.400 360.040 496.000 361.440 ;
        RECT 3.990 358.040 496.000 360.040 ;
        RECT 4.400 356.640 496.000 358.040 ;
        RECT 3.990 344.440 496.000 356.640 ;
        RECT 3.990 343.040 495.600 344.440 ;
        RECT 3.990 337.640 496.000 343.040 ;
        RECT 3.990 336.240 495.600 337.640 ;
        RECT 3.990 334.240 496.000 336.240 ;
        RECT 4.400 332.840 495.600 334.240 ;
        RECT 3.990 327.440 496.000 332.840 ;
        RECT 4.400 326.040 496.000 327.440 ;
        RECT 3.990 313.840 496.000 326.040 ;
        RECT 3.990 312.440 495.600 313.840 ;
        RECT 3.990 310.440 496.000 312.440 ;
        RECT 3.990 309.040 495.600 310.440 ;
        RECT 3.990 307.040 496.000 309.040 ;
        RECT 4.400 305.640 495.600 307.040 ;
        RECT 3.990 303.640 496.000 305.640 ;
        RECT 4.400 302.240 495.600 303.640 ;
        RECT 3.990 300.240 496.000 302.240 ;
        RECT 3.990 298.840 495.600 300.240 ;
        RECT 3.990 296.840 496.000 298.840 ;
        RECT 3.990 295.440 495.600 296.840 ;
        RECT 3.990 293.440 496.000 295.440 ;
        RECT 3.990 292.040 495.600 293.440 ;
        RECT 3.990 290.040 496.000 292.040 ;
        RECT 4.400 288.640 495.600 290.040 ;
        RECT 3.990 286.640 496.000 288.640 ;
        RECT 3.990 285.240 495.600 286.640 ;
        RECT 3.990 283.240 496.000 285.240 ;
        RECT 3.990 281.840 495.600 283.240 ;
        RECT 3.990 279.840 496.000 281.840 ;
        RECT 4.400 278.440 496.000 279.840 ;
        RECT 3.990 276.440 496.000 278.440 ;
        RECT 4.400 275.040 495.600 276.440 ;
        RECT 3.990 273.040 496.000 275.040 ;
        RECT 4.400 271.640 496.000 273.040 ;
        RECT 3.990 259.440 496.000 271.640 ;
        RECT 4.400 258.040 495.600 259.440 ;
        RECT 3.990 256.040 496.000 258.040 ;
        RECT 4.400 254.640 495.600 256.040 ;
        RECT 3.990 252.640 496.000 254.640 ;
        RECT 3.990 251.240 495.600 252.640 ;
        RECT 3.990 249.240 496.000 251.240 ;
        RECT 3.990 247.840 495.600 249.240 ;
        RECT 3.990 245.840 496.000 247.840 ;
        RECT 3.990 244.440 495.600 245.840 ;
        RECT 3.990 242.440 496.000 244.440 ;
        RECT 3.990 241.040 495.600 242.440 ;
        RECT 3.990 239.040 496.000 241.040 ;
        RECT 4.400 237.640 495.600 239.040 ;
        RECT 3.990 235.640 496.000 237.640 ;
        RECT 3.990 234.240 495.600 235.640 ;
        RECT 3.990 232.240 496.000 234.240 ;
        RECT 4.400 230.840 495.600 232.240 ;
        RECT 3.990 228.840 496.000 230.840 ;
        RECT 4.400 227.440 495.600 228.840 ;
        RECT 3.990 225.440 496.000 227.440 ;
        RECT 4.400 224.040 495.600 225.440 ;
        RECT 3.990 222.040 496.000 224.040 ;
        RECT 4.400 220.640 495.600 222.040 ;
        RECT 3.990 218.640 496.000 220.640 ;
        RECT 3.990 217.240 495.600 218.640 ;
        RECT 3.990 215.240 496.000 217.240 ;
        RECT 3.990 213.840 495.600 215.240 ;
        RECT 3.990 211.840 496.000 213.840 ;
        RECT 3.990 210.440 495.600 211.840 ;
        RECT 3.990 208.440 496.000 210.440 ;
        RECT 3.990 207.040 495.600 208.440 ;
        RECT 3.990 205.040 496.000 207.040 ;
        RECT 3.990 203.640 495.600 205.040 ;
        RECT 3.990 198.240 496.000 203.640 ;
        RECT 3.990 196.840 495.600 198.240 ;
        RECT 3.990 167.640 496.000 196.840 ;
        RECT 3.990 166.240 495.600 167.640 ;
        RECT 3.990 147.240 496.000 166.240 ;
        RECT 3.990 145.840 495.600 147.240 ;
        RECT 3.990 130.240 496.000 145.840 ;
        RECT 4.400 128.840 495.600 130.240 ;
        RECT 3.990 126.840 496.000 128.840 ;
        RECT 4.400 125.440 496.000 126.840 ;
        RECT 3.990 120.040 496.000 125.440 ;
        RECT 3.990 118.640 495.600 120.040 ;
        RECT 3.990 99.640 496.000 118.640 ;
        RECT 4.400 98.240 495.600 99.640 ;
        RECT 3.990 72.440 496.000 98.240 ;
        RECT 3.990 71.040 495.600 72.440 ;
        RECT 3.990 62.240 496.000 71.040 ;
        RECT 3.990 60.840 495.600 62.240 ;
        RECT 3.990 48.640 496.000 60.840 ;
        RECT 4.400 47.240 496.000 48.640 ;
        RECT 3.990 45.240 496.000 47.240 ;
        RECT 3.990 43.840 495.600 45.240 ;
        RECT 3.990 41.840 496.000 43.840 ;
        RECT 3.990 40.440 495.600 41.840 ;
        RECT 3.990 24.840 496.000 40.440 ;
        RECT 4.400 23.440 495.600 24.840 ;
        RECT 3.990 21.440 496.000 23.440 ;
        RECT 4.400 20.040 495.600 21.440 ;
        RECT 3.990 18.040 496.000 20.040 ;
        RECT 3.990 16.640 495.600 18.040 ;
        RECT 3.990 10.715 496.000 16.640 ;
      LAYER met4 ;
        RECT 23.295 19.895 23.940 485.345 ;
        RECT 26.340 19.895 174.240 485.345 ;
        RECT 176.640 19.895 177.540 485.345 ;
        RECT 179.940 19.895 327.840 485.345 ;
        RECT 330.240 19.895 331.140 485.345 ;
        RECT 333.540 19.895 481.440 485.345 ;
        RECT 483.840 19.895 484.740 485.345 ;
        RECT 487.140 19.895 488.225 485.345 ;
  END
END spi_host_lite
END LIBRARY

